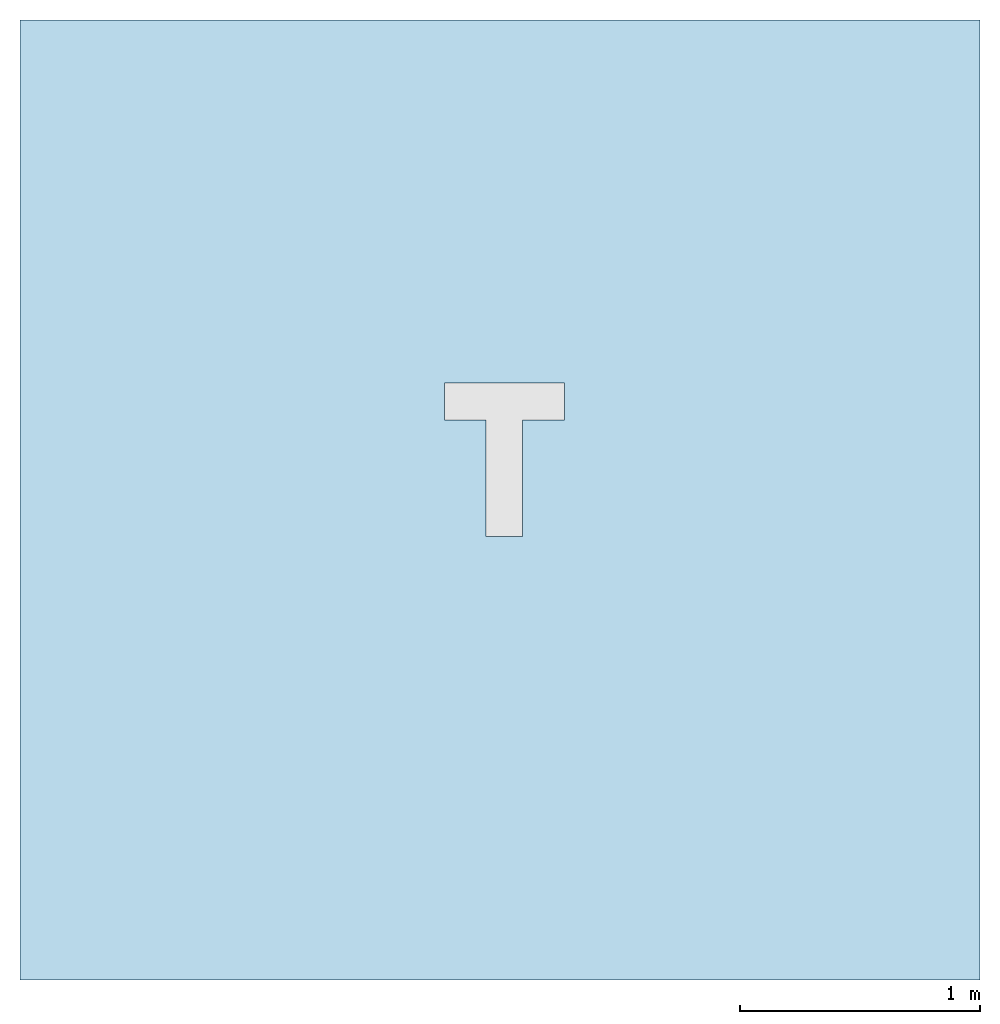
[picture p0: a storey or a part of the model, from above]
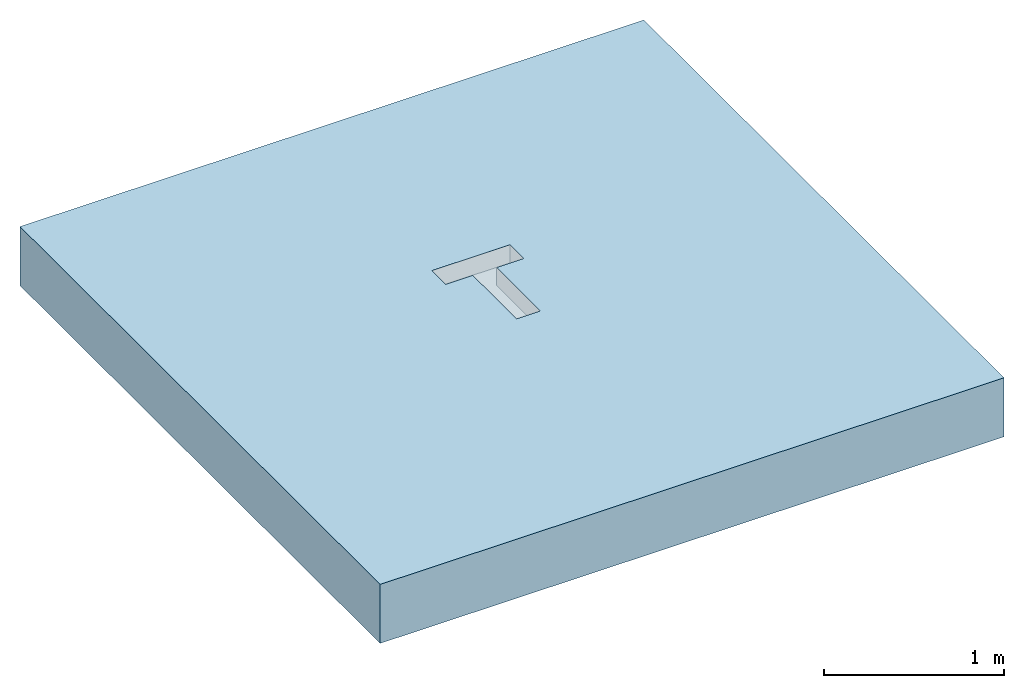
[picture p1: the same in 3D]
Properties of the parts of a building model (IFC2X3)

# File
Description: ViewDefinition [CoordinationView]
File name: 105225 - Branch Unit Channel - 500mm LG - Invert Depth 110mm.ifc
Time: 2014-03-20T10:30:16
Written by: Autodesk Revit 2013
Made in: 20120221_2030(x64)

# IfcProject, Project Number
LongName: Project Name; Phase: Project Status

# IfcSite, Default
RefLatitude: 42, 21, 30, 344238; RefLongitude: -71, -3, -35, -194702; RefElevation: 0 mm

# IfcBuilding
Pset_BuildingCommon - NumberOfStoreys: 1
Other - Project Status: Project Status; Project Name: Project Name; Project Address: ## Street City, State Zip; Client Name: Owner; Project Number: Project Number; Project Issue Date: Issue Date

# IfcBuildingStorey, Level 1
LongName: Level 1; Elevation: 0 mm
Constraints - Elevation Base: 0; Elevation: 0 mm
Graphics - Symbol at End 1 Default: no; Color: 0; Symbol: M_Level Head - Circle: M_Level Head - Circle; Line Weight: 1; Symbol at End 2 Default: yes; Line Pattern: Center
Dimensions - Computation Height: 0 mm
Identity Data - Structural: no; Building Story: yes; Name: Level 1

# IfcFlowTerminal: 105225 - Branch Unit Channel - 500mm LG - Invert Depth 110mm, ACO BD Modular 125 Branch Units:105225 - Branch Unit Channel - 500mm LG - Invert Depth 110mm:105225 - Branch Unit Channel - 500mm LG - Invert Depth 110mm:216444
In: Level 1
Material: Stainless Steel AISI 304 (F), Polystyrene, High Impact
Construction - 26270_PVC Infill: yes; 105844 - Slip Resistant Quadrato Locked - Stainless Steel 304 - 500mm long: no; 21920 - Grating - Plain Mesh - Stainless Steel 304 - 500mm long: no; 10735 - Composite - White Composite - 500mm long: no; 105519 - Slotted Locked - Stainless Steel 304 - 500mm long: no; 96819 - Grating - Heal Safe - Stainless Steel 304 - 500mm long: no; 105846 - Slip Resistant Intercept - Stainless Steel 304 - 500mm long: no; 105528 - Quadrato Locked - Stainless Steel 304 - 500mm long: no; 105521 - Slotted Locked - Stainless Steel 304 - 500mm long: no; End Plate Invert: no; 49061 & 49062_Vinyl Seal: no; 21720 - Grating - Plain Mesh - Stainless Steel 304 - 500mm long: no; 105842 - Slip Resistant Quadrato - Stainless Steel 304 - 500mm long: no; 105537 - Intercept Locked - Stainless Steel 304 - 500mm long: no; End Plate Invert Right Hand: no; 21910 - Grating - Slip Resistant Mesh - Stainless Steel 304 - 500mm long: no; 402072- Grating - Heal Safe Locked - Stainless Steel 304 - 500mm long: no; 21710 - Grating - Slip Resistant Mesh - Stainless Steel 304 - 500mm long: no; 105848 - Slip Resistant Intercept Locked - Stainless Steel 304 - 500mm long: no; 105530 - Quadrato - Stainless Steel 304 - 500mm long: no; 21740 - - Ladder - Stainless Steel 304 - 500mm long: no; 105539 - Intercept - Stainless Steel 304 - 500mm long: no; 15704 - Composite - Black Composite - 500mm long: no; End Plate Invert Left Hand: no; 105505 - Perforated Locked - Stainless Steel 304 - 500mm long: no; 21790 - Plastic - White Plastic - 500mm long: no; Detail 65mm: no; Detail 80mm: no; Detail 95mm: no; Detail 110mm: yes; Detail 50mm: no; Grating: yes; Detail 125mm: no
Phasing - Phase Created: New Construction
Identity Data - Mark: 3; Watermark2: This file is water marked and users are prohibited to reproduce, adapt, distribute this information; Fax: +44 (0)1462 851490; Address: ACO Business Centre, Caxton Road, Bedford, MK41 0LF; Telephone: +44 (0)1462 816666; Manufacturer: ACO Building Drainage; Website: www.acobd.com; Watermarked With: BIM Manager Premium Suite; Watermark1: This file is the property of ACO Technologies PLC; E-mail Technical: abdtechnical@aco.co.uk; Watermarked By: www.acobd.com; E-mail Sales: abdcommercial@aco.co.uk
Other - Rigid PVC Extrusion (49061): 0 mm; Flexible PVC Seal (49062): 0 mm; Neoprene Gasket: 2; PVC Infill (26270): 1847 mm
Dimensions - Depth: 89 mm; Void Invert Depth: 122.8 mm; Grating Height: 21 mm; Invert Depth: 110 mm
Constraints - Level: Level: Level 1; Moves With Nearby Elements: no
General - Channel Recyclable: Fully recyclable; Product Standard: BS EN 1433:2002, CE marked; Channel Recycled Material Content: 60-70%; Channel Material: Stainless Steel Grade 304; Dimensions (LxWxH): 500 x 639 x 110; Seal Recyclable: Fully recyclable; Weight (Kg): 5.4; Channel Colour: Mid Grey; Installation guidelines: X:\Electronic Literature\ABD Electronic Literature\Standard Stainless Steel and Galvanised Steel Channels\ACO Modular 125\ACO Modular 125.pdf; Product Code: 105225; NBS Specification: NBS Section Q10 Kerbs/edgings/channels/paving accessories, Clause 180 Drainage Channel Systems; Load Class: A15 - C250; Product Description: ACO Modular 125 500mm Branch Unit; Price: POA - contact ACO; Product Type: Stainless Steel Channel Drainage System; Seal Recycled Material Content: 0%; Maintenance guidelines: X:\Electronic Literature\ABD Electronic Literature\Standard Stainless Steel and Galvanised Steel Channels\ACO Modular 125\ACO Modular 125.pdf; Product Range: ACO Modular 125; Seal Colour: Black; Seal Material: Neoprene
Model Properties - Grating Product Code 105539: Load Class A15 - Intercept - Stainless Steel 304 - 500mm long - 1.8kg; Grating Product Code 402072: Load Class B125 - Heal Safe Locked - Stainless Steel 304 - 500mm long - 2.0kg; End Plate Product Code 105101: N/A; Grating Product Code 10735: Load Class C250 - Composite - White Composite - 500mm long - 1.2kg; Grating Product Code 105528: Load Class A15 - Quadrato Locked - Stainless Steel 304 - 500mm long - 1.6kg; Grating Product Code 105537: Load Class A15 - Intercept Locked - Stainless Steel 304 - 500mm long - 1.8kg; Grating Product Code 105844: Load Class A15 - Slip Resistant Quadrato Locked - Stainless Steel 304 - 500mm long - 1.6kg; End Plate Product Code 105105: N/A; End Plate Product Code 105103: N/A; Grating Product Code 21920: Load Class C250 - Plain Mesh - Stainless Steel 304 - 500mm long - 2.2kg; End Plate Product Code 105100: N/A; Grating Product Code 105848: Load Class A15 - Slip Resistant Intercept Locked - Stainless Steel 304 - 500mm long - 1.8kg; Grating Product Code 21740: Load Class C250 - Ladder - Stainless Steel 304 - 500mm long - 2.0kg; Grating Product Code 105519: Load Class A15 - Slotted Locked - Stainless Steel 304 - 500mm long - 1.0kg; Grating Product Code 105530: Load Class A15 - Quadrato - Stainless Steel 304 - 500mm long - 1.6kg; Grating Product Code 21710: Load Class A15 - Slip Resistant Mesh - Stainless Steel 304 - 500mm long - 1.6kg; Grating Product Code 96819: Load Class B125 - Heal Safe - Stainless Steel 304 - 500mm long - 2.0kg; End Plate Product Code 105102: N/A; Grating Product Code 105842: Load Class A15 - Slip Resistant Quadrato - Stainless Steel 304 - 500mm long - 1.6kg; Grating Product Code 15704: Load Class C250 - Composite - Black Composite - 500mm long - 1.2kg; End Plate Product Code 105104: End Plate Stainless Steel 304 for Invert Depth - 110mm - 0.26Kg; Grating Product Code 21790: Load Class A15 - Plastic - White Plastic - 500mm long - 0.6kg; Grating Product Code 105521: Load Class C250 - Slotted Locked - Stainless Steel 304 - 500mm long - 2.3kg; Grating Product Code 105846: Load Class A15 - Slip Resistant Intercept - Stainless Steel 304 - 500mm long - 1.8kg; Grating Product Code 21720: Load Class A15 - Plain Mesh - Stainless Steel 304 - 500mm long - 1.6kg; Grating Product Code 21910: Load Class C250 - Slip Resistant Mesh - Stainless Steel 304 - 500mm long - 2.2kg; Grating Product Code 105505: Load Class C250 - Perforated Locked - Stainless Steel 304 - 500mm long - 1.8kg

# IfcOpeningElement: Recess
In: Level 1
Dimensions - Area: 16000000 mm2; Thickness: 400 mm; Volume: 6381474637 mm3; Perimeter: 16000 mm
Constraints - Level: Level: Level 1; Related to Mass: no; Height Offset From Level: 0 mm; Room Bounding: yes
Phasing - Phase Created: New Construction
Structural - Structural: no; Enable Analytical Model: no
Graphics - Coarse Scale Fill Color: 0
Analytical Properties - Roughness: 1; Thermal mass: 604440; Heat Transfer Coefficient (U): 2.615; Thermal Resistance (R): 0.382409; Absorptance: 0.1
Construction - Function: 0; Default Thickness: 400 mm
Materials and Finishes - Structural Material: Concrete, Broom Finish

# IfcSlab: Floor:Generic Floor - 400mm, Floor:Generic Floor - 400mm:193825
In: Level 1
PredefinedType: FLOOR; Material: Concrete, Broom Finish 400 mm
Dimensions - Area: 16000000 mm2; Thickness: 400 mm; Volume: 6381474637 mm3; Perimeter: 16000 mm
Constraints - Level: Level: Level 1; Related to Mass: no; Height Offset From Level: 0 mm; Room Bounding: yes
Phasing - Phase Created: New Construction
Structural - Structural: no; Enable Analytical Model: no
Pset_SlabCommon - Reference: Generic Floor - 400mm; IsExternal: no; LoadBearing: yes
Graphics - Coarse Scale Fill Color: 0
Analytical Properties - Roughness: 1; Thermal mass: 604440; Heat Transfer Coefficient (U): 2.615; Thermal Resistance (R): 0.382409; Absorptance: 0.1
Construction - Function: 0; Default Thickness: 400 mm
Materials and Finishes - Structural Material: Concrete, Broom Finish
